// positive edge detection
PROGRAM p05_posEdge
VAR
	S0: BOOL;
	M0: BOOL;
	M1: BOOL;
END_VAR

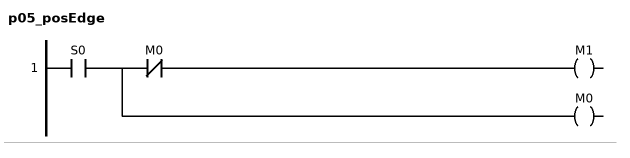
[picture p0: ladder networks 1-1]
// NETWORK 1
M1 := S0 AND NOT M0;
M0 := S0;

END_PROGRAM
